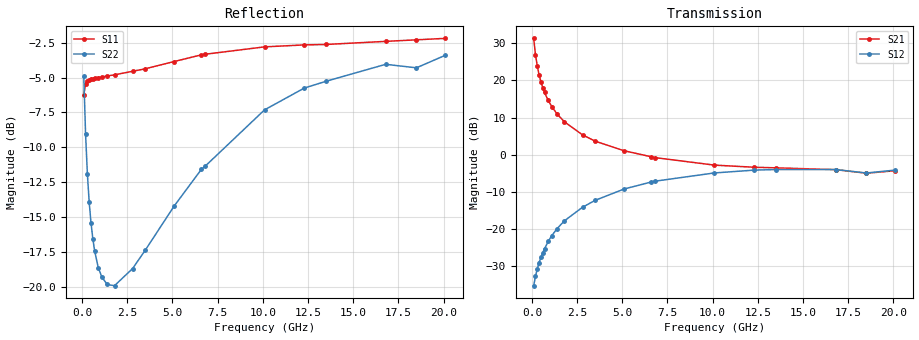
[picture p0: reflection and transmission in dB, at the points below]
!  Infineon Technologies AG
! BFR380L3 , PF131585-7, No.6, Th 09.10.01, soldered on pcb-board, measured with PP GSG850
!  Vce=4.0 V,  Ic=80.0 mA
! Common Emitter S-Parameters:  15. November 2001
#  GHz  S  MA  R  50
! f  S11  S21  S12  S22
! GHz  Mag  Ang  Mag  Ang  Mag  Ang  Mag  Ang
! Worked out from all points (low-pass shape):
!   201 points, 100 MHz to 20.1 GHz, reference 50 ohm
!   highest |S21| = 31.29 dB at 100 MHz (marker M1); lowest = -4.9 dB at 18.5 GHz (marker M2)
!   |S21| within 3 dB of the highest: start of sweep to 168.5 MHz
!   lowest |S11| = -6.2 dB at 100 MHz (marker M3), VSWR 2.91, Z = 24.3 - j29.5 ohm
!   |S11| at or under -10 dB: nowhere
!   |S22| runs from -20.0 to -3.4 dB; largest |S21 - S12| = 37
!   S11 on the Smith chart (normalised r, x): 100 MHz: 0.49, -0.59; 400 MHz: 0.29, -0.12; 2.8 GHz: 0.28, +0.30; 6.6 GHz: 0.31, +0.78; 12.3 GHz: 0.53, +1.51; 20.1 GHz: 1.08, +2.56
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0.1  0.4887 -109.4  36.67 129.5  0.01745 58.2  0.5699 -47.4
0.2  0.5314 -142.3  22.14 110.4  0.02338 57.1  0.3523 -63.7
0.3  0.5466 -156.5  15.48 101.7  0.02954 59.8  0.2534 -69.8
0.4  0.5521 -164.5  11.84 96.3  0.03567 63.0  0.2008 -73.0
0.5  0.5559 -170.0  9.546 92.3  0.04184 65.2  0.1692 -75.2
0.6  0.5564 -174.3  8.002 89.3  0.04852 67.1  0.1487 -76.8
0.7  0.5598 -177.6  6.892 86.5  0.05476 68.3  0.1344 -78.4
0.9  0.5623 176.9  5.395 81.9  0.06849 69.6  0.117 -81.2
1.1  0.5648 172.5  4.441 77.9  0.08196 70.1  0.1081 -85.0
1.4  0.5701 166.4  3.521 72.5  0.1023 69.9  0.1017 -90.7
1.8  0.5751 159.6  2.773 65.8  0.1298 68.9  0.1007 -99.3
2.8  0.5924 144.4  1.854 51.0  0.1973 63.8  0.116 -122.2
3.5  0.6047 134.9  1.525 41.8  0.2446 59.3  0.135 -135.2
5.1  0.6421 116.1  1.134 24.0  0.3471 48.1  0.1945 -164.8
6.6  0.6785 100.8  0.9416 11.3  0.4312 37.5  0.2631 171.3
6.8  0.6818 98.8  0.9177 9.8  0.4419 35.9  0.2698 168.5
10.1  0.7248 74.0  0.7268 -8.3  0.5709 12.7  0.4307 131.1
12.3  0.7367 62.6  0.6807 -16.9  0.6228 -1.7  0.5157 109.9
13.5  0.7394 57.0  0.668 -22.0  0.634 -9.1  0.5454 100.5
16.8  0.7585 45.9  0.6321 -32.4  0.6345 -25.3  0.6275 78.0
18.5  0.7683 44.1  0.5661 -39.7  0.5695 -33.7  0.6096 72.3
20.1  0.7776 37.3  0.6109 -43.3  0.6233 -39.0  0.6762 61.2
